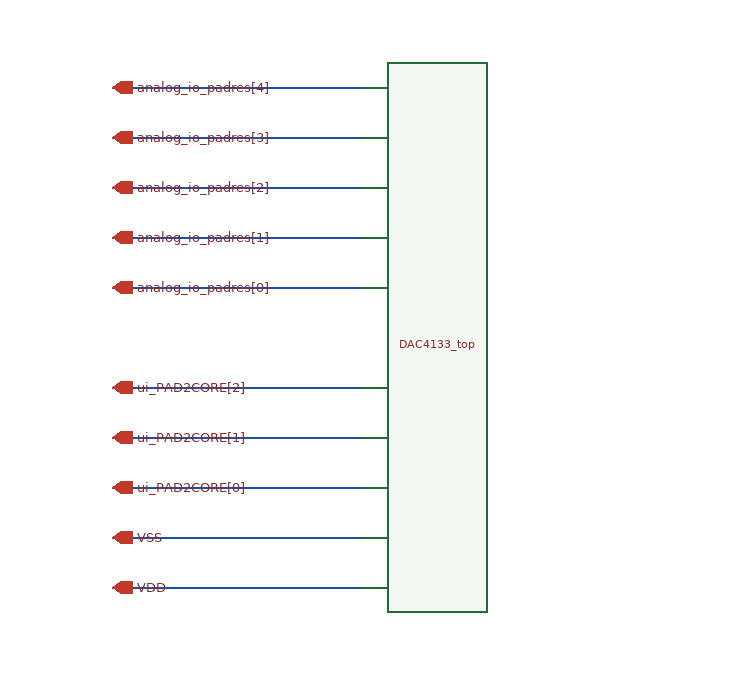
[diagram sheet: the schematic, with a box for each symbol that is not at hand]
v {xschem version=3.4.8RC file_version=1.3}
G {}
K {}
V {}
S {}
F {}
E {}
N -350 -210 -150 -210 {lab=analog_io_padres[4]}
N -350 -170 -150 -170 {lab=analog_io_padres[3]}
N -350 -130 -150 -130 {lab=analog_io_padres[2]}
N -350 -90 -150 -90 {lab=analog_io_padres[1]}
N -350 -50 -150 -50 {lab=analog_io_padres[0]}
N -350 30 -150 30 {lab=ui_PAD2CORE[2]}
N -350 70 -150 70 {lab=ui_PAD2CORE[1]}
N -350 110 -150 110 {lab=ui_PAD2CORE[1]}
N -350 150 -150 150 {lab=VSS}
N -350 190 -150 190 {lab=VDD}
C {DAC4133_top.sym} 0 -10 0 0 {}
C {iopin.sym} -350 150 0 1 {name=p1 lab=VSS}
C {iopin.sym} -350 190 0 1 {name=p2 lab=VDD}
C {iopin.sym} -350 70 0 1 {name=p3 lab=ui_PAD2CORE[1]}
C {iopin.sym} -350 110 0 1 {name=p4 lab=ui_PAD2CORE[0]}
C {iopin.sym} -350 30 0 1 {name=p6 lab=ui_PAD2CORE[2]}
C {iopin.sym} -350 -90 0 1 {name=p7 lab=analog_io_padres[1]}
C {iopin.sym} -350 -50 0 1 {name=p8 lab=analog_io_padres[0]}
C {iopin.sym} -350 -170 0 1 {name=p9 lab=analog_io_padres[3]}
C {iopin.sym} -350 -130 0 1 {name=p10 lab=analog_io_padres[2]}
C {iopin.sym} -350 -210 0 1 {name=p12 lab=analog_io_padres[4]}
